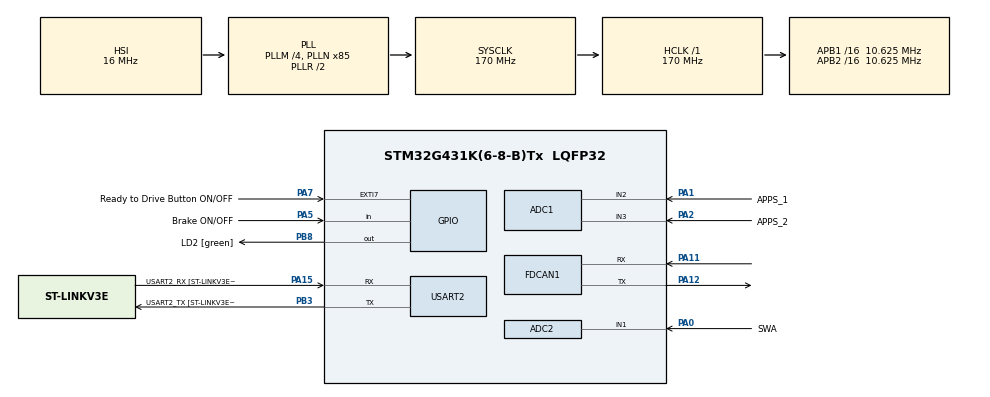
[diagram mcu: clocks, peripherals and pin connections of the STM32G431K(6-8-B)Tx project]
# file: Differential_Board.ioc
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ADC1.Channel-1\#ChannelRegularConversion=ADC_CHANNEL_2
ADC1.Channel-2\#ChannelRegularConversion=ADC_CHANNEL_3
ADC1.ClockPrescaler=ADC_CLOCK_ASYNC_DIV8
ADC1.ContinuousConvMode=ENABLE
ADC1.DMAContinuousRequests=DISABLE
ADC1.NbrOfConversion=2
ADC1.NbrOfConversionFlag=1
ADC1.OffsetNumber-1\#ChannelRegularConversion=ADC_OFFSET_NONE
ADC1.OffsetNumber-2\#ChannelRegularConversion=ADC_OFFSET_NONE
ADC1.Overrun=ADC_OVR_DATA_OVERWRITTEN
ADC1.Rank-1\#ChannelRegularConversion=1
ADC1.Rank-2\#ChannelRegularConversion=2
ADC1.SamplingTime-1\#ChannelRegularConversion=ADC_SAMPLETIME_24CYCLES_5
ADC1.SamplingTime-2\#ChannelRegularConversion=ADC_SAMPLETIME_24CYCLES_5
ADC1.master=1
ADC2.Channel-0\#ChannelRegularConversion=ADC_CHANNEL_1
ADC2.ClockPrescaler=ADC_CLOCK_ASYNC_DIV8
ADC2.ContinuousConvMode=ENABLE
ADC2.NbrOfConversionFlag=1
ADC2.OffsetNumber-0\#ChannelRegularConversion=ADC_OFFSET_NONE
ADC2.Overrun=ADC_OVR_DATA_OVERWRITTEN
ADC2.Rank-0\#ChannelRegularConversion=1
ADC2.SamplingTime-0\#ChannelRegularConversion=ADC_SAMPLETIME_2CYCLES_5
FDCAN1.NominalTimeSeg1=4
Mcu.Family=STM32G4
Mcu.Name=STM32G431K(6-8-B)Tx
Mcu.Package=LQFP32
NVIC.EXTI9_5_IRQn=true\:0\:0\:false\:false\:true\:true\:true
NVIC.FDCAN1_IT0_IRQn=true\:0\:0\:false\:false\:true\:true\:true
NVIC.PriorityGroup=NVIC_PRIORITYGROUP_4
NVIC.TIM1_BRK_TIM15_IRQn=true\:0\:0\:false\:false\:true\:true\:true
NVIC.TIM1_CC_IRQn=true\:0\:0\:false\:false\:true\:true\:true
NVIC.TIM1_TRG_COM_TIM17_IRQn=true\:0\:0\:false\:false\:true\:true\:true
NVIC.TIM1_UP_TIM16_IRQn=true\:0\:0\:false\:false\:true\:true\:true
NVIC.TIM2_IRQn=true\:0\:0\:false\:false\:true\:true\:true
PA0.GPIO_Label=SWA
PA0.Mode=IN1-Single-Ended
PA0.Signal=ADC2_IN1
PA1.GPIO_Label=APPS_1
PA1.Mode=IN2-Single-Ended
PA1.Signal=ADC1_IN2
PA11.Mode=FDCANMaster
PA11.Signal=FDCAN1_RX
PA12.Mode=FDCANMaster
PA12.Signal=FDCAN1_TX
PA13.GPIO_Label=T_SWDIO
PA13.Mode=Serial_Wire
PA13.Signal=SYS_JTMS-SWDIO
PA14.GPIO_Label=T_SWCLK
PA14.Mode=Serial_Wire
PA14.Signal=SYS_JTCK-SWCLK
PA15.GPIO_Label=USART2_RX [ST-LINKV3E_VCP_TX]
PA15.Mode=Asynchronous
PA15.Signal=USART2_RX
PA2.GPIO_Label=APPS_2
PA2.Mode=IN3-Single-Ended
PA2.Signal=ADC1_IN3
PA5.GPIO_Label=Brake ON/OFF
PA5.Signal=GPIO_Input
PA7.GPIO_Label=Ready to Drive Button ON/OFF
PA7.GPIO_ModeDefaultEXTI=GPIO_MODE_IT_FALLING
PA7.Signal=GPXTI7
PB3.GPIO_Label=USART2_TX [ST-LINKV3E_VCP_RX]
PB3.Mode=Asynchronous
PB3.Signal=USART2_TX
PB8-BOOT0.GPIO_Label=LD2 [green]
PB8-BOOT0.Signal=GPIO_Output
ProjectManager.HeapSize=0x200
ProjectManager.StackSize=0x400
ProjectManager.TargetToolchain=STM32CubeIDE
RCC.ADC12Freq_Value=170000000
RCC.AHBFreq_Value=170000000
RCC.APB1CLKDivider=RCC_HCLK_DIV16
RCC.APB1Freq_Value=10625000
RCC.APB1TimFreq_Value=21250000
RCC.APB2CLKDivider=RCC_HCLK_DIV16
RCC.APB2Freq_Value=10625000
RCC.APB2TimFreq_Value=21250000
RCC.CortexFreq_Value=170000000
RCC.EXTERNAL_CLOCK_VALUE=12288000
RCC.HCLKFreq_Value=170000000
RCC.HSE_VALUE=8000000
RCC.HSI48_VALUE=48000000
RCC.HSI_VALUE=16000000
RCC.LSE_VALUE=32768
RCC.PLLM=RCC_PLLM_DIV4
RCC.PLLN=85
RCC.SYSCLKFreq_VALUE=170000000
RCC.SYSCLKSource=RCC_SYSCLKSOURCE_PLLCLK
RCC.USBFreq_Value=170000000
RCC.VCOOutputFreq_Value=340000000
TIM1.PeriodNoDither=50
TIM1.Prescaler=21250
TIM2.PeriodNoDither=100
TIM2.Prescaler=21250
USART2.VirtualMode-Asynchronous=VM_ASYNC
USART2.WordLength=WORDLENGTH_8B
VP_SYS_VS_DBSignals.Mode=DisableDeadBatterySignals
VP_TIM1_VS_ClockSourceINT.Mode=Internal
VP_TIM2_VS_ClockSourceINT.Mode=Internal
board=NUCLEO-G431KB

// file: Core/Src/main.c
/* USER CODE BEGIN Header */
/**
  ******************************************************************************
  * @file           : main.c
  * @brief          : Main program body
  ******************************************************************************
  * @attention
  *
  * <h2><center>&copy; Copyright (c) 2020 STMicroelectronics.
  * All rights reserved.</center></h2>
  *
  * This software component is licensed by ST under BSD 3-Clause license,
  * the "License"; You may not use this file except in compliance with the
  * License. You may obtain a copy of the License at:
  *                        opensource.org/licenses/BSD-3-Clause
  *
  ******************************************************************************
  */
/* USER CODE END Header */

#include "main.h"

/* USER CODE BEGIN Includes */
#include "stdbool.h"
#include "Differential_Code.c"
#include "math.h"
/* USER CODE END Includes */

ADC_HandleTypeDef hadc1;
ADC_HandleTypeDef hadc2;

FDCAN_HandleTypeDef hfdcan1;

TIM_HandleTypeDef htim1;
TIM_HandleTypeDef htim2;

UART_HandleTypeDef huart2;

/* USER CODE BEGIN PV */
bool Ready_to_Drive_FLAG = false;
bool Implausibility_Flag = false;
bool Tractive_System_ON_FLAG = true; //flag para saber se o sistema de tracao esta ativo
uint32_t Brake_value[10] = {0};
uint32_t APPS_value[10] = {0};//10 for the APPS1 sensor
uint32_t APPS2_value[10] = {0};//10 for the APPS1 sensor
uint32_t buffer[3];
uint8_t RxData[16];
uint8_t RxDataExpected[] = {0x10, 0x32, 0x54, 0x76, 0x98, 0x00, 0x11, 0x22, 0x33, 0x44, 0x55, 0x66, 0x77, 0x88, 0x99, 0x00};
uint8_t ErrorMessage[] = {0x00, 0x00, 0x00, 0xFF, 0xFF, 0xFF, 0x00, 0x00, 0x00};
uint8_t L = 1.7;
uint8_t D = 1.19;

float Rotations[2] = {0};
volatile float SWA_value_Average;
volatile float Brake_value_Average;
volatile float APPS1_value_Average;
volatile float APPS2_value_Average;
volatile float APPS_Result;
volatile float SWA_Result;
volatile uint32_t Right_Motor_Rotation;
volatile uint32_t Left_Motor_Rotation;
static FDCAN_RxHeaderTypeDef RxMessage;
static FDCAN_TxHeaderTypeDef TxMessage;
/* USER CODE END PV */

void SystemClock_Config(void);
static void MX_GPIO_Init(void);
static void MX_USART2_UART_Init(void);
static void MX_FDCAN1_Init(void);
static void MX_ADC1_Init(void);
static void MX_TIM1_Init(void);
static void MX_TIM2_Init(void);
static void MX_ADC2_Init(void);
/* USER CODE BEGIN PFP */
void (*Pos_pointer)();

//prototypes:
void Init_State(); //State after the turn-on, waiting for the ready to drive start;
void Comm_State(); //State which the car is on the ready to drive mode;
//void Error_State(); //State which whenever error occours.

void CAN_Filter_Config(void);
/* USER CODE END PFP */

int main(void)
{

  /* MCU Configuration--------------------------------------------------------*/

  /* Reset of all peripherals, Initializes the Flash interface and the Systick. */
  HAL_Init();

  /* USER CODE BEGIN Init */
  HAL_FDCAN_Start(&hfdcan1);
  /* USER CODE END Init */

  /* Configure the system clock */
  SystemClock_Config();

  /* Initialize all configured peripherals */
  MX_GPIO_Init();
  MX_USART2_UART_Init();
  MX_FDCAN1_Init();
  MX_ADC1_Init();
  MX_TIM1_Init();
  MX_TIM2_Init();
  MX_ADC2_Init();
  /* USER CODE BEGIN 2 */
  Pos_pointer = Init_State;

  HAL_ADC_Start_IT(&hadc1);
  HAL_ADC_Start_IT(&hadc2);

 // HAL_FDCAN_Init(&hfdcan);

  /* USER CODE END 2 */

  /* Infinite loop */
  /* USER CODE BEGIN WHILE */
  while (1)
  {
	  (*Pos_pointer)();
	 // HAL_Delay(500);
	  //debug:
	 // HAL_GPIO_TogglePin(LD2_GPIO_Port, LD2_Pin);
	  //debug:
	  Tractive_System_ON_FLAG = true; //System must wait for this CAN command.

    /* USER CODE END WHILE */

  }
}

void SystemClock_Config(void)
{
  RCC_OscInitTypeDef RCC_OscInitStruct = {0};
  RCC_ClkInitTypeDef RCC_ClkInitStruct = {0};
  RCC_PeriphCLKInitTypeDef PeriphClkInit = {0};

  /** Configure the main internal regulator output voltage
  */
  HAL_PWREx_ControlVoltageScaling(PWR_REGULATOR_VOLTAGE_SCALE1_BOOST);
  /** Initializes the CPU, AHB and APB busses clocks
  */
  RCC_OscInitStruct.OscillatorType = RCC_OSCILLATORTYPE_HSI;
  RCC_OscInitStruct.HSIState = RCC_HSI_ON;
  RCC_OscInitStruct.HSICalibrationValue = RCC_HSICALIBRATION_DEFAULT;
  RCC_OscInitStruct.PLL.PLLState = RCC_PLL_ON;
  RCC_OscInitStruct.PLL.PLLSource = RCC_PLLSOURCE_HSI;
  RCC_OscInitStruct.PLL.PLLM = RCC_PLLM_DIV4;
  RCC_OscInitStruct.PLL.PLLN = 85;
  RCC_OscInitStruct.PLL.PLLP = RCC_PLLP_DIV2;
  RCC_OscInitStruct.PLL.PLLQ = RCC_PLLQ_DIV2;
  RCC_OscInitStruct.PLL.PLLR = RCC_PLLR_DIV2;
  if (HAL_RCC_OscConfig(&RCC_OscInitStruct) != HAL_OK)
  {
    Error_Handler();
  }
  /** Initializes the CPU, AHB and APB busses clocks
  */
  RCC_ClkInitStruct.ClockType = RCC_CLOCKTYPE_HCLK|RCC_CLOCKTYPE_SYSCLK
                              |RCC_CLOCKTYPE_PCLK1|RCC_CLOCKTYPE_PCLK2;
  RCC_ClkInitStruct.SYSCLKSource = RCC_SYSCLKSOURCE_PLLCLK;
  RCC_ClkInitStruct.AHBCLKDivider = RCC_SYSCLK_DIV1;
  RCC_ClkInitStruct.APB1CLKDivider = RCC_HCLK_DIV16;
  RCC_ClkInitStruct.APB2CLKDivider = RCC_HCLK_DIV16;

  if (HAL_RCC_ClockConfig(&RCC_ClkInitStruct, FLASH_LATENCY_8) != HAL_OK)
  {
    Error_Handler();
  }
  /** Initializes the peripherals clocks
  */
  PeriphClkInit.PeriphClockSelection = RCC_PERIPHCLK_USART2|RCC_PERIPHCLK_ADC12
                              |RCC_PERIPHCLK_FDCAN;
  PeriphClkInit.Usart2ClockSelection = RCC_USART2CLKSOURCE_PCLK1;
  PeriphClkInit.FdcanClockSelection = RCC_FDCANCLKSOURCE_PCLK1;
  PeriphClkInit.Adc12ClockSelection = RCC_ADC12CLKSOURCE_SYSCLK;
  if (HAL_RCCEx_PeriphCLKConfig(&PeriphClkInit) != HAL_OK)
  {
    Error_Handler();
  }
}

static void MX_ADC1_Init(void)
{

  ADC_MultiModeTypeDef multimode = {0};
  ADC_ChannelConfTypeDef sConfig = {0};

  /** Common config
  */
  hadc1.Instance = ADC1;
  hadc1.Init.ClockPrescaler = ADC_CLOCK_ASYNC_DIV8;
  hadc1.Init.Resolution = ADC_RESOLUTION_12B;
  hadc1.Init.DataAlign = ADC_DATAALIGN_RIGHT;
  hadc1.Init.GainCompensation = 0;
  hadc1.Init.ScanConvMode = ADC_SCAN_ENABLE;
  hadc1.Init.EOCSelection = ADC_EOC_SINGLE_CONV;
  hadc1.Init.LowPowerAutoWait = DISABLE;
  hadc1.Init.ContinuousConvMode = ENABLE;
  hadc1.Init.NbrOfConversion = 2;
  hadc1.Init.DiscontinuousConvMode = DISABLE;
  hadc1.Init.ExternalTrigConv = ADC_SOFTWARE_START;
  hadc1.Init.ExternalTrigConvEdge = ADC_EXTERNALTRIGCONVEDGE_NONE;
  hadc1.Init.DMAContinuousRequests = DISABLE;
  hadc1.Init.Overrun = ADC_OVR_DATA_OVERWRITTEN;
  hadc1.Init.OversamplingMode = DISABLE;
  if (HAL_ADC_Init(&hadc1) != HAL_OK)
  {
    Error_Handler();
  }
  /** Configure the ADC multi-mode
  */
  multimode.Mode = ADC_MODE_INDEPENDENT;
  if (HAL_ADCEx_MultiModeConfigChannel(&hadc1, &multimode) != HAL_OK)
  {
    Error_Handler();
  }
  /** Configure Regular Channel
  */
  sConfig.Channel = ADC_CHANNEL_2;
  sConfig.Rank = ADC_REGULAR_RANK_1;
  sConfig.SamplingTime = ADC_SAMPLETIME_24CYCLES_5;
  sConfig.SingleDiff = ADC_SINGLE_ENDED;
  sConfig.OffsetNumber = ADC_OFFSET_NONE;
  sConfig.Offset = 0;
  if (HAL_ADC_ConfigChannel(&hadc1, &sConfig) != HAL_OK)
  {
    Error_Handler();
  }
  /** Configure Regular Channel
  */
  sConfig.Channel = ADC_CHANNEL_3;
  sConfig.Rank = ADC_REGULAR_RANK_2;
  if (HAL_ADC_ConfigChannel(&hadc1, &sConfig) != HAL_OK)
  {
    Error_Handler();
  }

}

static void MX_ADC2_Init(void)
{

  ADC_ChannelConfTypeDef sConfig = {0};

  /** Common config
  */
  hadc2.Instance = ADC2;
  hadc2.Init.ClockPrescaler = ADC_CLOCK_ASYNC_DIV8;
  hadc2.Init.Resolution = ADC_RESOLUTION_12B;
  hadc2.Init.DataAlign = ADC_DATAALIGN_RIGHT;
  hadc2.Init.GainCompensation = 0;
  hadc2.Init.ScanConvMode = ADC_SCAN_DISABLE;
  hadc2.Init.EOCSelection = ADC_EOC_SINGLE_CONV;
  hadc2.Init.LowPowerAutoWait = DISABLE;
  hadc2.Init.ContinuousConvMode = ENABLE;
  hadc2.Init.NbrOfConversion = 1;
  hadc2.Init.DiscontinuousConvMode = DISABLE;
  hadc2.Init.ExternalTrigConv = ADC_SOFTWARE_START;
  hadc2.Init.ExternalTrigConvEdge = ADC_EXTERNALTRIGCONVEDGE_NONE;
  hadc2.Init.DMAContinuousRequests = DISABLE;
  hadc2.Init.Overrun = ADC_OVR_DATA_OVERWRITTEN;
  hadc2.Init.OversamplingMode = DISABLE;
  if (HAL_ADC_Init(&hadc2) != HAL_OK)
  {
    Error_Handler();
  }
  /** Configure Regular Channel
  */
  sConfig.Channel = ADC_CHANNEL_1;
  sConfig.Rank = ADC_REGULAR_RANK_1;
  sConfig.SamplingTime = ADC_SAMPLETIME_2CYCLES_5;
  sConfig.SingleDiff = ADC_SINGLE_ENDED;
  sConfig.OffsetNumber = ADC_OFFSET_NONE;
  sConfig.Offset = 0;
  if (HAL_ADC_ConfigChannel(&hadc2, &sConfig) != HAL_OK)
  {
    Error_Handler();
  }

}

static void MX_FDCAN1_Init(void)
{

  hfdcan1.Instance = FDCAN1;
  hfdcan1.Init.ClockDivider = FDCAN_CLOCK_DIV1;
  hfdcan1.Init.FrameFormat = FDCAN_FRAME_FD_NO_BRS;
  hfdcan1.Init.Mode = FDCAN_MODE_NORMAL;
  hfdcan1.Init.AutoRetransmission = DISABLE;
  hfdcan1.Init.TransmitPause = DISABLE;
  hfdcan1.Init.ProtocolException = DISABLE;
  hfdcan1.Init.NominalPrescaler = 1;
  hfdcan1.Init.NominalSyncJumpWidth = 1;
  hfdcan1.Init.NominalTimeSeg1 = 4;
  hfdcan1.Init.NominalTimeSeg2 = 2;
  hfdcan1.Init.DataPrescaler = 1;
  hfdcan1.Init.DataSyncJumpWidth = 1;
  hfdcan1.Init.DataTimeSeg1 = 1;
  hfdcan1.Init.DataTimeSeg2 = 1;
  hfdcan1.Init.StdFiltersNbr = 0;
  hfdcan1.Init.ExtFiltersNbr = 0;
  hfdcan1.Init.TxFifoQueueMode = FDCAN_TX_FIFO_OPERATION;
  if (HAL_FDCAN_Init(&hfdcan1) != HAL_OK)
  {
    Error_Handler();
  }
  /* USER CODE BEGIN FDCAN1_Init 2 */

	  TxMessage.Identifier = 0x111;
	  TxMessage.IdType = FDCAN_STANDARD_ID;
	  TxMessage.TxFrameType = FDCAN_DATA_FRAME;
	  TxMessage.DataLength = FDCAN_DLC_BYTES_8;
	  TxMessage.ErrorStateIndicator = FDCAN_ESI_ACTIVE;
	  TxMessage.BitRateSwitch = FDCAN_BRS_ON;
	  TxMessage.FDFormat = FDCAN_FD_CAN;
	  TxMessage.TxEventFifoControl = FDCAN_NO_TX_EVENTS;
	  TxMessage.MessageMarker = 0;

  /* USER CODE END FDCAN1_Init 2 */

}

static void MX_TIM1_Init(void)
{

  TIM_ClockConfigTypeDef sClockSourceConfig = {0};
  TIM_MasterConfigTypeDef sMasterConfig = {0};
  TIM_BreakDeadTimeConfigTypeDef sBreakDeadTimeConfig = {0};

  htim1.Instance = TIM1;
  htim1.Init.Prescaler = 21250;
  htim1.Init.CounterMode = TIM_COUNTERMODE_UP;
  htim1.Init.Period = 50;
  htim1.Init.ClockDivision = TIM_CLOCKDIVISION_DIV1;
  htim1.Init.RepetitionCounter = 0;
  htim1.Init.AutoReloadPreload = TIM_AUTORELOAD_PRELOAD_DISABLE;
  if (HAL_TIM_Base_Init(&htim1) != HAL_OK)
  {
    Error_Handler();
  }
  sClockSourceConfig.ClockSource = TIM_CLOCKSOURCE_INTERNAL;
  if (HAL_TIM_ConfigClockSource(&htim1, &sClockSourceConfig) != HAL_OK)
  {
    Error_Handler();
  }
  sMasterConfig.MasterOutputTrigger = TIM_TRGO_RESET;
  sMasterConfig.MasterOutputTrigger2 = TIM_TRGO2_RESET;
  sMasterConfig.MasterSlaveMode = TIM_MASTERSLAVEMODE_DISABLE;
  if (HAL_TIMEx_MasterConfigSynchronization(&htim1, &sMasterConfig) != HAL_OK)
  {
    Error_Handler();
  }
  sBreakDeadTimeConfig.BreakAFMode = TIM_BREAK_AFMODE_INPUT;
  sBreakDeadTimeConfig.Break2AFMode = TIM_BREAK_AFMODE_INPUT;
  if (HAL_TIMEx_ConfigBreakDeadTime(&htim1, &sBreakDeadTimeConfig) != HAL_OK)
  {
    Error_Handler();
  }

}

static void MX_TIM2_Init(void)
{

  TIM_ClockConfigTypeDef sClockSourceConfig = {0};
  TIM_MasterConfigTypeDef sMasterConfig = {0};

  htim2.Instance = TIM2;
  htim2.Init.Prescaler = 21250;
  htim2.Init.CounterMode = TIM_COUNTERMODE_UP;
  htim2.Init.Period = 100;
  htim2.Init.ClockDivision = TIM_CLOCKDIVISION_DIV1;
  htim2.Init.AutoReloadPreload = TIM_AUTORELOAD_PRELOAD_DISABLE;
  if (HAL_TIM_Base_Init(&htim2) != HAL_OK)
  {
    Error_Handler();
  }
  sClockSourceConfig.ClockSource = TIM_CLOCKSOURCE_INTERNAL;
  if (HAL_TIM_ConfigClockSource(&htim2, &sClockSourceConfig) != HAL_OK)
  {
    Error_Handler();
  }
  sMasterConfig.MasterOutputTrigger = TIM_TRGO_RESET;
  sMasterConfig.MasterSlaveMode = TIM_MASTERSLAVEMODE_DISABLE;
  if (HAL_TIMEx_MasterConfigSynchronization(&htim2, &sMasterConfig) != HAL_OK)
  {
    Error_Handler();
  }

}

static void MX_USART2_UART_Init(void)
{

  huart2.Instance = USART2;
  huart2.Init.BaudRate = 115200;
  huart2.Init.WordLength = UART_WORDLENGTH_8B;
  huart2.Init.StopBits = UART_STOPBITS_1;
  huart2.Init.Parity = UART_PARITY_NONE;
  huart2.Init.Mode = UART_MODE_TX_RX;
  huart2.Init.HwFlowCtl = UART_HWCONTROL_NONE;
  huart2.Init.OverSampling = UART_OVERSAMPLING_16;
  huart2.Init.OneBitSampling = UART_ONE_BIT_SAMPLE_DISABLE;
  huart2.Init.ClockPrescaler = UART_PRESCALER_DIV1;
  huart2.AdvancedInit.AdvFeatureInit = UART_ADVFEATURE_NO_INIT;
  if (HAL_UART_Init(&huart2) != HAL_OK)
  {
    Error_Handler();
  }
  if (HAL_UARTEx_SetTxFifoThreshold(&huart2, UART_TXFIFO_THRESHOLD_1_8) != HAL_OK)
  {
    Error_Handler();
  }
  if (HAL_UARTEx_SetRxFifoThreshold(&huart2, UART_RXFIFO_THRESHOLD_1_8) != HAL_OK)
  {
    Error_Handler();
  }
  if (HAL_UARTEx_DisableFifoMode(&huart2) != HAL_OK)
  {
    Error_Handler();
  }

}

static void MX_GPIO_Init(void)
{
  GPIO_InitTypeDef GPIO_InitStruct = {0};

  /* GPIO Ports Clock Enable */
  __HAL_RCC_GPIOA_CLK_ENABLE();
  __HAL_RCC_GPIOB_CLK_ENABLE();

  /*Configure GPIO pin Output Level */
  HAL_GPIO_WritePin(GPIOA, BrakeRangesOK_Pin|Buzzer_Pin, GPIO_PIN_RESET);

  /*Configure GPIO pin Output Level */
  HAL_GPIO_WritePin(LD2_GPIO_Port, LD2_Pin, GPIO_PIN_RESET);

  /*Configure GPIO pin : Brake_ON_OFF_Pin */
  GPIO_InitStruct.Pin = Brake_ON_OFF_Pin;
  GPIO_InitStruct.Mode = GPIO_MODE_INPUT;
  GPIO_InitStruct.Pull = GPIO_NOPULL;
  HAL_GPIO_Init(Brake_ON_OFF_GPIO_Port, &GPIO_InitStruct);

  /*Configure GPIO pin : Ready_to_Drive_Button_ON_OFF_Pin */
  GPIO_InitStruct.Pin = Ready_to_Drive_Button_ON_OFF_Pin;
  GPIO_InitStruct.Mode = GPIO_MODE_IT_FALLING;
  GPIO_InitStruct.Pull = GPIO_NOPULL;
  HAL_GPIO_Init(Ready_to_Drive_Button_ON_OFF_GPIO_Port, &GPIO_InitStruct);

  /*Configure GPIO pins : BrakeRangesOK_Pin Buzzer_Pin */
  GPIO_InitStruct.Pin = BrakeRangesOK_Pin|Buzzer_Pin;
  GPIO_InitStruct.Mode = GPIO_MODE_OUTPUT_PP;
  GPIO_InitStruct.Pull = GPIO_NOPULL;
  GPIO_InitStruct.Speed = GPIO_SPEED_FREQ_LOW;
  HAL_GPIO_Init(GPIOA, &GPIO_InitStruct);

  /*Configure GPIO pin : LD2_Pin */
  GPIO_InitStruct.Pin = LD2_Pin;
  GPIO_InitStruct.Mode = GPIO_MODE_OUTPUT_PP;
  GPIO_InitStruct.Pull = GPIO_NOPULL;
  GPIO_InitStruct.Speed = GPIO_SPEED_FREQ_LOW;
  HAL_GPIO_Init(LD2_GPIO_Port, &GPIO_InitStruct);

  /* EXTI interrupt init*/
  HAL_NVIC_SetPriority(EXTI9_5_IRQn, 3, 0);
  HAL_NVIC_EnableIRQ(EXTI9_5_IRQn);

}

/* USER CODE BEGIN 4 */

void Ackermann_Equation(float APPS_Result, float SWA_Result, float *Rotations)
{
	uint32_t Actual_Rot = APPS_Result*300;

	Rotations[0] = Actual_Rot*(1 + ((D/2)*tan(SWA_Result))/L);
	Rotations[1] = Actual_Rot*(1 - ((D/2)*tan(SWA_Result))/L);
}

//Detects Ready to drive button interrupt (GPIO_PIN_7)
void HAL_GPIO_EXTI_Callback(uint16_t GPIO_Pin)
{

	if((GPIO_Pin == GPIO_PIN_7) && (Tractive_System_ON_FLAG == true) && (HAL_GPIO_ReadPin(Brake_ON_OFF_GPIO_Port,Brake_ON_OFF_Pin) == GPIO_PIN_SET) && (Ready_to_Drive_FLAG == false))
	{
		HAL_TIM_Base_Start_IT(&htim1);

	} else{
		__NOP();
		//(*Pos_pointer)();
	}

	//debug
	/*
	if((GPIO_Pin == GPIO_PIN_7))
	{
		HAL_GPIO_WritePin(LD2_GPIO_Port, LD2_Pin, GPIO_PIN_SET);
		HAL_TIM_Base_Start_IT(&htim1);
	}else{
		__NOP();
		//(*Pos_pointer)();
	}
	//debug
	 *
	 */
}

void Debouncing_Check()
{

/*
  //If Ready to Drive button and brake remain pressed..Set the Ready to Drive Mode flag to True.
	if((HAL_GPIO_ReadPin(GPIOA,GPIO_PIN_7) == GPIO_PIN_SET) && (HAL_GPIO_ReadPin(Brake_ON_OFF_GPIO_Port,Brake_ON_OFF_Pin) == GPIO_PIN_SET) ){
		Ready_to_Drive_FLAG = true;
		HAL_TIM_Base_Stop_IT(&htim1);
	}
	*/
  if((HAL_GPIO_ReadPin(GPIOA,GPIO_PIN_7) == GPIO_PIN_SET) && (HAL_GPIO_ReadPin(Brake_ON_OFF_GPIO_Port,Brake_ON_OFF_Pin) == GPIO_PIN_SET))
	{
	  HAL_GPIO_WritePin(LD2_GPIO_Port, LD2_Pin, GPIO_PIN_RESET);
	  Ready_to_Drive_FLAG = true;
	} else{
		(*Pos_pointer)();
	}
}

static uint32_t BufferCmp8b(uint8_t* pBuffer1, uint8_t* pBuffer2, uint16_t BufferLength)
{
  while(BufferLength--)
  {
    if(*pBuffer1 != *pBuffer2)
    {
      return 1;
    }

    pBuffer1++;
    pBuffer2++;
  }
  return 0;
}

void Init_State(void)
{

	 while (HAL_FDCAN_GetRxFifoFillLevel(&hfdcan1, FDCAN_RX_FIFO0) < 2) {}

	    /* Retreive Rx messages from RX FIFO0 */
	    HAL_FDCAN_GetRxMessage(&hfdcan1, FDCAN_RX_FIFO0, &RxMessage, RxData);
	    HAL_FDCAN_GetRxMessage(&hfdcan1, FDCAN_RX_FIFO0, &RxMessage, &RxData[8]);

	    if (BufferCmp8b(RxDataExpected, RxData, 16) != 0)
	      {
	    	Pos_pointer = Error_Handler;
	      }
	    else
	    {
	    	Pos_pointer = Comm_State;

	    	//Turn on buzzer 2 seconds
	    	HAL_GPIO_WritePin(Buzzer_GPIO_Port, Buzzer_Pin, GPIO_PIN_SET);
	    	HAL_Delay(2000);
	    	HAL_GPIO_WritePin(Buzzer_GPIO_Port, Buzzer_Pin, GPIO_PIN_RESET);
	    }

	//Check if the Ready to Drive Mode Flag is true.
}

void Comm_State(void)
{
	for( int i=0; i <10; i++)
	{
	HAL_ADC_Start(&hadc1);
	HAL_ADC_Start(&hadc2);
	HAL_ADC_PollForConversion(&hadc2, 100);
	Brake_value_Average += 0.1*HAL_ADC_GetValue(&hadc2);
	//SWA recebe via CAN

	HAL_ADC_PollForConversion(&hadc1, 100);
	APPS1_value_Average += 0.1*HAL_ADC_GetValue(&hadc1);

	HAL_ADC_PollForConversion(&hadc1, 100);
	APPS2_value_Average += 0.1*HAL_ADC_GetValue(&hadc1);

	HAL_ADC_Stop (&hadc1);
	HAL_ADC_Stop(&hadc2);
	}

	//Transform to voltage
    Brake_value_Average = (Brake_value_Average*3.3)/4095;
	APPS1_value_Average = (APPS1_value_Average*3.3)/4095;
	APPS2_value_Average = (APPS2_value_Average*3.3)/4095;

	//APPS2_value_Average -= 0.5; //Value used to remove APPS2 offset

 if(((APPS1_value_Average) == 0.0)||((APPS2_value_Average) == 0.0)||((APPS2_value_Average) > 3.29)||((APPS1_value_Average) > 3.29))
		{
			//If a short circuit or open circuit occurs... a flag is set
		 	 	HAL_TIM_Base_Start_IT(&htim2);
		}

 if(((APPS1_value_Average - APPS2_value_Average) > 0.1)||((APPS2_value_Average - APPS1_value_Average) > 0.1))
	{
		//If a deviation more than 10% occurs between the sensors... a flag is set
	 	 	HAL_TIM_Base_Start_IT(&htim2);
	}

 APPS_Result = APPS1_value_Average + APPS2_value_Average;

 if(((Brake_value_Average) == 0.0)||((Brake_value_Average) > 3.29))
		{
			//If a short circuit or open circuit occurs... a flag is set
	 	 	 	 HAL_GPIO_WritePin(BrakeRangesOK_GPIO_Port, BrakeRangesOK_Pin, GPIO_PIN_RESET);
		 	 	HAL_TIM_Base_Start_IT(&htim2);
		}else{
				HAL_GPIO_WritePin(BrakeRangesOK_GPIO_Port, BrakeRangesOK_Pin, GPIO_PIN_SET);
		}

 if(((Brake_value_Average) > 0.5)&&((APPS_Result) > 0.825))
		{
			//If brake is pressed and apps > 25%... a flag is set
		 	 	HAL_TIM_Base_Start_IT(&htim2);
		}

 	 //add formula calculo diferencial
 	 Ackermann_Equation(APPS_Result, SWA_Result, Rotations);

 	 HAL_FDCAN_Start(&hfdcan1);

 	 HAL_FDCAN_AddMessageToTxFifoQ(&hfdcan1, &TxMessage, &Rotations[0]);
 	HAL_FDCAN_AddMessageToTxFifoQ(&hfdcan1, &TxMessage, &Rotations[1]);

 	 //HAL_FDCAN_Stop(&hfdcan1);
}

void Implausibility_Check()
{
	if(((APPS1_value_Average - APPS2_value_Average) > 0.1)||((APPS2_value_Average - APPS1_value_Average) > 0.1))
		{
			//If a deviation more than 10% occurs between the sensors... a flag is set
		 		Pos_pointer = Error_Handler;
		}

	 if(((APPS1_value_Average) == 0.0)||((APPS2_value_Average) == 0.0)||((APPS2_value_Average) > 3.29)||((APPS1_value_Average) > 3.29))
			{
				//If a short circuit or open circuit occurs... a flag is set
		 	 	 Pos_pointer = Error_Handler;
			}

	 if(((Brake_value_Average) == 0.0)||((Brake_value_Average) > 3.29))
			{
				//If a short circuit or open circuit occurs... a flag is set
		 	 	 Pos_pointer = Error_Handler;
			}
}

HAL_TIM_PeriodElapsedCallback(TIM_HandleTypeDef *htim)
{
     if(htim->Instance==TIM1)
         {
    	 	 Debouncing_Check();
         }

      if(htim->Instance==TIM2)
         {
    	  	  Implausibility_Check();
         }
}

/* USER CODE END 4 */

void Error_Handler(void)
{
  /* USER CODE BEGIN Error_Handler_Debug */
  /* User can add his own implementation to report the HAL error return state */

	HAL_FDCAN_AddMessageToTxFifoQ(&hfdcan1, &TxMessage, &ErrorMessage);
  /* USER CODE END Error_Handler_Debug */
}

/************************ (C) COPYRIGHT STMicroelectronics *****END OF FILE****/
